VERSION 5.8 ;
BUSBITCHARS "[]" ;
DIVIDERCHAR "/" ;
UNITS
    DATABASE MICRONS 1000 ;
END UNITS

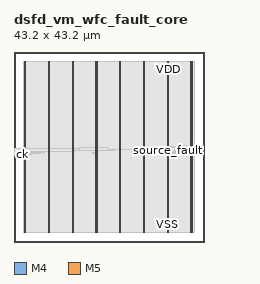
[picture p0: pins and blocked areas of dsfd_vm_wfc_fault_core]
MACRO dsfd_vm_wfc_fault_core
  FOREIGN dsfd_vm_wfc_fault_core 0 0 ;
  CLASS BLOCK ;
  SIZE 43.2 BY 43.2 ;
  PIN ck
    DIRECTION INPUT ;
    USE SIGNAL ;
    PORT
      LAYER M4 ;
        RECT  0 19.824 0.084 19.848 ;
    END
  END ck
  PIN core_fault
    DIRECTION INPUT ;
    USE SIGNAL ;
    PORT
      LAYER M4 ;
        RECT  0 19.92 0.084 19.944 ;
    END
  END core_fault
  PIN core_fault_b
    DIRECTION INPUT ;
    USE SIGNAL ;
    PORT
      LAYER M4 ;
        RECT  0 20.016 0.084 20.04 ;
    END
  END core_fault_b
  PIN remote_fault
    DIRECTION INPUT ;
    USE SIGNAL ;
    PORT
      LAYER M4 ;
        RECT  0 20.112 0.084 20.136 ;
    END
  END remote_fault
  PIN rn
    DIRECTION INPUT ;
    USE SIGNAL ;
    PORT
      LAYER M4 ;
        RECT  0 20.208 0.084 20.232 ;
    END
  END rn
  PIN source_fault
    DIRECTION OUTPUT ;
    USE SIGNAL ;
    PORT
      LAYER M4 ;
        RECT  43.116 20.784 43.2 20.808 ;
    END
  END source_fault
  PIN summary
    DIRECTION OUTPUT ;
    USE SIGNAL ;
    PORT
      LAYER M4 ;
        RECT  43.116 20.88 43.2 20.904 ;
    END
  END summary
  PIN transfer_fault
    DIRECTION INPUT ;
    USE SIGNAL ;
    PORT
      LAYER M4 ;
        RECT  0 20.304 0.084 20.328 ;
    END
  END transfer_fault
  PIN tx_valid
    DIRECTION OUTPUT ;
    USE SIGNAL ;
    PORT
      LAYER M4 ;
        RECT  43.116 20.976 43.2 21 ;
    END
  END tx_valid
  PIN VDD
    DIRECTION INOUT ;
    USE POWER ;
    PORT
      LAYER M5 ;
        RECT  40.392 2.151 40.512 41.049 ;
        RECT  34.992 2.151 35.112 41.049 ;
        RECT  29.592 2.151 29.712 41.049 ;
        RECT  24.192 2.151 24.312 41.049 ;
        RECT  18.792 2.151 18.912 41.049 ;
        RECT  13.392 2.151 13.512 41.049 ;
        RECT  7.992 2.151 8.112 41.049 ;
        RECT  2.592 2.151 2.712 41.049 ;
    END
  END VDD
  PIN VSS
    DIRECTION INOUT ;
    USE GROUND ;
    PORT
      LAYER M5 ;
        RECT  40.2 2.137 40.32 41.063 ;
        RECT  34.8 2.137 34.92 41.063 ;
        RECT  29.4 2.137 29.52 41.063 ;
        RECT  24 2.137 24.12 41.063 ;
        RECT  18.6 2.137 18.72 41.063 ;
        RECT  13.2 2.137 13.32 41.063 ;
        RECT  7.8 2.137 7.92 41.063 ;
        RECT  2.4 2.137 2.52 41.063 ;
    END
  END VSS
  # OT_OBS_CLOSED layer=M5 d_um=1.536 added=2
  OBS
    LAYER RVTN ;
     RECT  2.16 2.16 41.04 2.295 ;
     RECT  2.16 2.565 41.04 2.835 ;
     RECT  2.16 3.105 41.04 3.375 ;
     RECT  2.16 3.645 41.04 3.915 ;
     RECT  2.16 4.185 41.04 4.455 ;
     RECT  2.16 4.725 41.04 4.995 ;
     RECT  2.16 5.265 41.04 5.535 ;
     RECT  2.16 5.805 41.04 6.075 ;
     RECT  2.16 6.345 41.04 6.615 ;
     RECT  2.16 6.885 41.04 7.155 ;
     RECT  2.16 7.425 41.04 7.695 ;
     RECT  2.16 7.965 41.04 8.235 ;
     RECT  2.16 8.505 41.04 8.775 ;
     RECT  2.16 9.045 41.04 9.315 ;
     RECT  2.16 9.585 41.04 9.855 ;
     RECT  2.16 10.125 41.04 10.395 ;
     RECT  2.16 10.665 41.04 10.935 ;
     RECT  2.16 11.205 41.04 11.475 ;
     RECT  2.16 11.745 41.04 12.015 ;
     RECT  2.16 12.285 41.04 12.555 ;
     RECT  2.16 12.825 41.04 13.095 ;
     RECT  2.16 13.365 41.04 13.635 ;
     RECT  2.16 13.905 41.04 14.175 ;
     RECT  2.16 14.445 41.04 14.715 ;
     RECT  2.16 14.985 41.04 15.255 ;
     RECT  2.16 15.525 41.04 15.795 ;
     RECT  2.16 16.065 41.04 16.335 ;
     RECT  2.16 16.605 41.04 16.875 ;
     RECT  2.16 17.145 41.04 17.415 ;
     RECT  2.16 17.685 41.04 17.955 ;
     RECT  2.16 18.225 41.04 18.495 ;
     RECT  2.16 18.765 41.04 19.035 ;
     RECT  2.16 19.305 41.04 19.575 ;
     RECT  2.16 19.845 41.04 20.115 ;
     RECT  2.16 20.385 41.04 20.655 ;
     RECT  2.16 20.925 41.04 21.195 ;
     RECT  2.16 21.465 41.04 21.735 ;
     RECT  2.16 22.005 41.04 22.275 ;
     RECT  2.16 22.545 41.04 22.815 ;
     RECT  2.16 23.085 41.04 23.355 ;
     RECT  2.16 23.625 41.04 23.895 ;
     RECT  2.16 24.165 41.04 24.435 ;
     RECT  2.16 24.705 41.04 24.975 ;
     RECT  2.16 25.245 41.04 25.515 ;
     RECT  2.16 25.785 41.04 26.055 ;
     RECT  2.16 26.325 41.04 26.595 ;
     RECT  2.16 26.865 41.04 27.135 ;
     RECT  2.16 27.405 41.04 27.675 ;
     RECT  2.16 27.945 41.04 28.215 ;
     RECT  2.16 28.485 41.04 28.755 ;
     RECT  2.16 29.025 41.04 29.295 ;
     RECT  2.16 29.565 41.04 29.835 ;
     RECT  2.16 30.105 41.04 30.375 ;
     RECT  2.16 30.645 41.04 30.915 ;
     RECT  2.16 31.185 41.04 31.455 ;
     RECT  2.16 31.725 41.04 31.995 ;
     RECT  2.16 32.265 41.04 32.535 ;
     RECT  2.16 32.805 41.04 33.075 ;
     RECT  2.16 33.345 41.04 33.615 ;
     RECT  2.16 33.885 41.04 34.155 ;
     RECT  2.16 34.425 41.04 34.695 ;
     RECT  2.16 34.965 41.04 35.235 ;
     RECT  2.16 35.505 41.04 35.775 ;
     RECT  2.16 36.045 41.04 36.315 ;
     RECT  2.16 36.585 41.04 36.855 ;
     RECT  2.16 37.125 41.04 37.395 ;
     RECT  2.16 37.665 41.04 37.935 ;
     RECT  2.16 38.205 41.04 38.475 ;
     RECT  2.16 38.745 41.04 39.015 ;
     RECT  2.16 39.285 41.04 39.555 ;
     RECT  2.16 39.825 41.04 40.095 ;
     RECT  2.16 40.365 41.04 40.635 ;
     RECT  2.16 40.905 41.04 41.04 ;
    LAYER RVTP ;
     RECT  2.16 2.295 41.04 2.565 ;
     RECT  2.16 2.835 41.04 3.105 ;
     RECT  2.16 3.375 41.04 3.645 ;
     RECT  2.16 3.915 41.04 4.185 ;
     RECT  2.16 4.455 41.04 4.725 ;
     RECT  2.16 4.995 41.04 5.265 ;
     RECT  2.16 5.535 41.04 5.805 ;
     RECT  2.16 6.075 41.04 6.345 ;
     RECT  2.16 6.615 41.04 6.885 ;
     RECT  2.16 7.155 41.04 7.425 ;
     RECT  2.16 7.695 41.04 7.965 ;
     RECT  2.16 8.235 41.04 8.505 ;
     RECT  2.16 8.775 41.04 9.045 ;
     RECT  2.16 9.315 41.04 9.585 ;
     RECT  2.16 9.855 41.04 10.125 ;
     RECT  2.16 10.395 41.04 10.665 ;
     RECT  2.16 10.935 41.04 11.205 ;
     RECT  2.16 11.475 41.04 11.745 ;
     RECT  2.16 12.015 41.04 12.285 ;
     RECT  2.16 12.555 41.04 12.825 ;
     RECT  2.16 13.095 41.04 13.365 ;
     RECT  2.16 13.635 41.04 13.905 ;
     RECT  2.16 14.175 41.04 14.445 ;
     RECT  2.16 14.715 41.04 14.985 ;
     RECT  2.16 15.255 41.04 15.525 ;
     RECT  2.16 15.795 41.04 16.065 ;
     RECT  2.16 16.335 41.04 16.605 ;
     RECT  2.16 16.875 41.04 17.145 ;
     RECT  2.16 17.415 41.04 17.685 ;
     RECT  2.16 17.955 41.04 18.225 ;
     RECT  2.16 18.495 41.04 18.765 ;
     RECT  2.16 19.035 41.04 19.305 ;
     RECT  2.16 19.575 41.04 19.845 ;
     RECT  2.16 20.115 41.04 20.385 ;
     RECT  2.16 20.655 41.04 20.925 ;
     RECT  2.16 21.195 41.04 21.465 ;
     RECT  2.16 21.735 41.04 22.005 ;
     RECT  2.16 22.275 41.04 22.545 ;
     RECT  2.16 22.815 41.04 23.085 ;
     RECT  2.16 23.355 41.04 23.625 ;
     RECT  2.16 23.895 41.04 24.165 ;
     RECT  2.16 24.435 41.04 24.705 ;
     RECT  2.16 24.975 41.04 25.245 ;
     RECT  2.16 25.515 41.04 25.785 ;
     RECT  2.16 26.055 41.04 26.325 ;
     RECT  2.16 26.595 41.04 26.865 ;
     RECT  2.16 27.135 41.04 27.405 ;
     RECT  2.16 27.675 41.04 27.945 ;
     RECT  2.16 28.215 41.04 28.485 ;
     RECT  2.16 28.755 41.04 29.025 ;
     RECT  2.16 29.295 41.04 29.565 ;
     RECT  2.16 29.835 41.04 30.105 ;
     RECT  2.16 30.375 41.04 30.645 ;
     RECT  2.16 30.915 41.04 31.185 ;
     RECT  2.16 31.455 41.04 31.725 ;
     RECT  2.16 31.995 41.04 32.265 ;
     RECT  2.16 32.535 41.04 32.805 ;
     RECT  2.16 33.075 41.04 33.345 ;
     RECT  2.16 33.615 41.04 33.885 ;
     RECT  2.16 34.155 41.04 34.425 ;
     RECT  2.16 34.695 41.04 34.965 ;
     RECT  2.16 35.235 41.04 35.505 ;
     RECT  2.16 35.775 41.04 36.045 ;
     RECT  2.16 36.315 41.04 36.585 ;
     RECT  2.16 36.855 41.04 37.125 ;
     RECT  2.16 37.395 41.04 37.665 ;
     RECT  2.16 37.935 41.04 38.205 ;
     RECT  2.16 38.475 41.04 38.745 ;
     RECT  2.16 39.015 41.04 39.285 ;
     RECT  2.16 39.555 41.04 39.825 ;
     RECT  2.16 40.095 41.04 40.365 ;
     RECT  2.16 40.635 41.04 40.905 ;
    LAYER M1 ;
     RECT  2.16 2.151 41.04 41.049 ;
    LAYER M2 ;
     RECT  2.16 2.151 41.04 41.049 ;
     RECT  41.04 20.736 42.179 21.924 ;
     RECT  42.179 21.906 43.115 21.924 ;
    LAYER M3 ;
     RECT  2.415 2.143 2.505 2.413 ;
     RECT  7.815 2.143 7.905 2.413 ;
     RECT  13.215 2.143 13.305 2.413 ;
     RECT  18.615 2.143 18.705 2.413 ;
     RECT  24.015 2.143 24.105 2.413 ;
     RECT  29.415 2.143 29.505 2.413 ;
     RECT  34.815 2.143 34.905 2.413 ;
     RECT  40.215 2.143 40.305 2.413 ;
     RECT  2.415 2.413 2.697 19.885 ;
     RECT  3.528 19.885 4.086 19.921 ;
     RECT  34.815 2.413 35.097 20.011 ;
     RECT  3.42 19.921 4.086 20.119 ;
     RECT  5.652 19.885 5.67 20.119 ;
     RECT  34.815 20.011 35.442 20.119 ;
     RECT  2.304 19.885 2.697 20.155 ;
     RECT  3.42 20.119 4.23 20.155 ;
     RECT  6.912 20.119 6.93 20.155 ;
     RECT  18.615 2.413 18.897 20.155 ;
     RECT  32.976 20.083 32.994 20.155 ;
     RECT  34.776 20.119 35.946 20.155 ;
     RECT  37.224 20.119 37.242 20.155 ;
     RECT  2.304 20.155 4.842 20.191 ;
     RECT  5.652 20.119 5.814 20.191 ;
     RECT  34.776 20.155 37.386 20.191 ;
     RECT  6.912 20.155 6.966 20.309 ;
     RECT  17.892 20.155 18.897 20.309 ;
     RECT  2.304 20.191 6.138 20.317 ;
     RECT  6.912 20.309 6.93 20.317 ;
     RECT  29.415 2.413 29.697 20.317 ;
     RECT  30.528 20.083 30.834 20.317 ;
     RECT  32.94 20.155 32.994 20.317 ;
     RECT  13.215 2.413 13.497 20.389 ;
     RECT  34.272 20.191 37.926 20.389 ;
     RECT  2.304 20.317 6.93 20.417 ;
     RECT  28.296 20.281 28.314 20.425 ;
     RECT  31.572 20.317 31.59 20.461 ;
     RECT  32.328 20.317 32.994 20.461 ;
     RECT  33.984 20.389 37.926 20.461 ;
     RECT  39.06 20.353 39.078 20.461 ;
     RECT  40.215 2.413 40.497 20.461 ;
     RECT  2.304 20.417 6.318 20.489 ;
     RECT  10.836 20.389 10.854 20.489 ;
     RECT  13.215 20.389 13.77 20.489 ;
     RECT  2.304 20.489 6.174 20.579 ;
     RECT  31.572 20.461 32.994 20.615 ;
     RECT  26.784 20.155 26.802 20.659 ;
     RECT  29.304 20.317 30.834 20.659 ;
     RECT  4.068 20.579 6.174 20.669 ;
     RECT  4.068 20.669 4.23 20.687 ;
     RECT  33.984 20.461 39.078 20.695 ;
     RECT  40.068 20.461 40.497 20.695 ;
     RECT  2.304 20.579 3.294 20.723 ;
     RECT  4.068 20.687 4.086 20.723 ;
     RECT  5.004 20.669 6.174 20.723 ;
     RECT  26.784 20.659 27.45 20.731 ;
     RECT  28.296 20.425 28.35 20.731 ;
     RECT  29.088 20.659 30.834 20.731 ;
     RECT  31.572 20.615 31.734 20.731 ;
     RECT  32.472 20.615 32.994 20.731 ;
     RECT  33.984 20.695 39.258 20.731 ;
     RECT  2.304 20.723 3.15 20.849 ;
     RECT  5.004 20.723 5.022 20.849 ;
     RECT  5.796 20.723 6.174 20.849 ;
     RECT  13.215 20.489 13.662 20.861 ;
     RECT  26.784 20.731 31.734 20.885 ;
     RECT  32.472 20.731 39.258 20.885 ;
     RECT  2.304 20.849 2.697 20.921 ;
     RECT  26.784 20.885 27.45 20.921 ;
     RECT  22.824 20.827 22.842 20.957 ;
     RECT  26.784 20.921 26.874 20.957 ;
     RECT  37.152 20.885 39.258 21.001 ;
     RECT  40.068 20.695 40.734 21.001 ;
     RECT  26.856 20.957 26.874 21.005 ;
     RECT  28.224 20.885 31.734 21.119 ;
     RECT  37.152 21.001 40.734 21.119 ;
     RECT  28.224 21.119 30.438 21.155 ;
     RECT  21.132 21.115 21.15 21.163 ;
     RECT  28.296 21.155 30.438 21.191 ;
     RECT  20.916 21.163 21.15 21.2 ;
     RECT  31.284 21.119 31.41 21.263 ;
     RECT  28.296 21.191 29.754 21.389 ;
     RECT  31.392 21.263 31.41 21.389 ;
     RECT  32.472 20.885 35.946 21.389 ;
     RECT  28.296 21.389 29.697 21.395 ;
     RECT  33.48 21.389 35.097 21.425 ;
     RECT  14.832 21.307 14.85 21.437 ;
     RECT  21.132 21.2 21.15 21.437 ;
     RECT  32.472 21.389 32.742 21.437 ;
     RECT  33.66 21.425 35.097 21.437 ;
     RECT  28.512 21.395 29.697 21.461 ;
     RECT  42.156 20.731 42.174 21.497 ;
     RECT  28.512 21.461 28.53 21.569 ;
     RECT  37.152 21.119 40.698 21.631 ;
     RECT  32.472 21.437 32.49 21.659 ;
     RECT  33.66 21.437 33.678 21.659 ;
     RECT  35.928 21.389 35.946 21.659 ;
     RECT  37.044 21.631 40.698 21.695 ;
     RECT  37.044 21.695 39.222 21.739 ;
     RECT  36.54 21.739 39.222 21.803 ;
     RECT  37.044 21.803 39.222 21.929 ;
     RECT  43.092 20.971 43.11 21.929 ;
     RECT  37.224 21.929 37.71 21.965 ;
     RECT  40.215 21.695 40.698 21.965 ;
     RECT  38.664 21.929 39.222 22.001 ;
     RECT  38.664 22.001 38.682 22.037 ;
     RECT  37.224 21.965 37.674 22.073 ;
     RECT  37.224 22.073 37.386 22.199 ;
     RECT  37.224 22.199 37.242 22.235 ;
     RECT  2.415 20.921 2.697 40.787 ;
     RECT  7.815 2.413 8.097 40.787 ;
     RECT  13.215 20.861 13.497 40.787 ;
     RECT  18.615 20.309 18.897 40.787 ;
     RECT  24.015 2.413 24.297 40.787 ;
     RECT  29.415 21.461 29.697 40.787 ;
     RECT  34.815 21.437 35.097 40.787 ;
     RECT  40.215 21.965 40.497 40.787 ;
     RECT  2.415 40.787 2.505 41.057 ;
     RECT  7.815 40.787 7.905 41.057 ;
     RECT  13.215 40.787 13.305 41.057 ;
     RECT  18.615 40.787 18.705 41.057 ;
     RECT  24.015 40.787 24.105 41.057 ;
     RECT  29.415 40.787 29.505 41.057 ;
     RECT  34.815 40.787 34.905 41.057 ;
     RECT  40.215 40.787 40.305 41.057 ;
    LAYER M4 ;
     RECT  0.084 19.824 0.133 19.848 ;
     RECT  0.06 19.848 0.133 19.92 ;
     RECT  0.084 19.92 0.133 19.944 ;
     RECT  0.06 19.944 0.133 20.016 ;
     RECT  0.084 20.016 0.133 20.04 ;
     RECT  0.06 20.04 0.133 20.112 ;
     RECT  0.084 20.112 0.133 20.136 ;
     RECT  0.06 20.136 0.133 20.208 ;
     RECT  0.084 20.208 0.133 20.232 ;
     RECT  0.06 20.232 0.133 20.304 ;
     RECT  0.084 20.304 0.133 20.328 ;
     RECT  0.133 19.824 0.179 21.192 ;
     RECT  0.179 19.92 2.408 21.192 ;
     RECT  2.408 2.148 2.512 41.052 ;
     RECT  2.512 2.418 2.704 40.782 ;
     RECT  2.704 20.64 7.808 21.192 ;
     RECT  7.808 2.148 7.912 41.052 ;
     RECT  7.912 2.418 8.104 40.782 ;
     RECT  8.104 20.64 13.208 21.192 ;
     RECT  13.208 2.148 13.312 41.052 ;
     RECT  13.312 2.418 13.504 40.782 ;
     RECT  13.504 20.448 13.667 21.336 ;
     RECT  13.667 20.832 14.821 21.336 ;
     RECT  14.821 20.832 18.608 21.432 ;
     RECT  18.608 2.148 18.712 41.052 ;
     RECT  18.712 2.418 18.904 40.782 ;
     RECT  18.904 20.832 21.161 21.432 ;
     RECT  21.161 20.832 22.853 21.144 ;
     RECT  22.853 20.928 24.008 21.144 ;
     RECT  24.008 2.148 24.112 41.052 ;
     RECT  24.112 2.418 24.304 40.782 ;
     RECT  24.304 20.928 26.829 21.144 ;
     RECT  26.829 20.976 26.869 21.144 ;
     RECT  26.869 20.976 26.915 21.384 ;
     RECT  26.915 21.12 29.269 21.384 ;
     RECT  29.269 20.352 29.408 21.384 ;
     RECT  29.408 2.148 29.512 41.052 ;
     RECT  29.512 2.418 29.704 40.782 ;
     RECT  29.704 20.448 31.532 21.192 ;
     RECT  31.532 20.352 31.573 21.192 ;
     RECT  31.573 20.352 31.619 21.432 ;
     RECT  31.619 21.408 34.808 21.432 ;
     RECT  34.808 2.148 34.912 41.052 ;
     RECT  34.912 2.418 35.104 40.782 ;
     RECT  35.104 20.304 35.219 21.432 ;
     RECT  35.219 20.448 35.273 20.712 ;
     RECT  35.273 20.688 36.529 20.712 ;
     RECT  36.529 20.496 37.289 20.712 ;
     RECT  37.289 20.688 37.793 20.712 ;
     RECT  36.517 21.744 37.973 21.768 ;
     RECT  40.208 2.148 40.312 41.052 ;
     RECT  40.312 2.418 40.504 40.782 ;
     RECT  42.145 20.784 43.081 20.904 ;
     RECT  43.081 20.784 43.116 20.808 ;
     RECT  43.081 20.808 43.164 20.88 ;
     RECT  43.081 20.88 43.116 20.904 ;
     RECT  43.081 20.904 43.164 20.976 ;
     RECT  43.081 20.976 43.116 21 ;
    LAYER M5 ;
     RECT  2.4 2.137 2.52 2.151 ;
     RECT  7.8 2.137 7.92 2.151 ;
     RECT  13.2 2.137 13.32 2.151 ;
     RECT  18.6 2.137 18.72 2.151 ;
     RECT  24 2.137 24.12 2.151 ;
     RECT  29.4 2.137 29.52 2.151 ;
     RECT  34.8 2.137 34.92 2.151 ;
     RECT  40.2 2.137 40.32 2.151 ;
     RECT  34.8 2.151 35.112 20.293 ;
     RECT  29.4 2.151 29.712 20.341 ;
     RECT  13.2 2.151 13.512 20.437 ;
     RECT  0.144 19.813 0.168 21.203 ;
     RECT  13.2 20.437 13.656 21.347 ;
     RECT  26.88 20.965 26.904 21.395 ;
     RECT  29.28 20.341 29.712 21.395 ;
     RECT  31.584 20.341 31.608 21.443 ;
     RECT  34.8 20.293 35.208 21.443 ;
     RECT  36.528 20.677 36.552 21.779 ;
     RECT  2.4 2.151 2.712 41.049 ;
     RECT  7.8 2.151 8.112 41.049 ;
     RECT  13.2 21.347 13.512 41.049 ;
     RECT  18.6 2.151 18.912 41.049 ;
     RECT  24 2.151 24.312 41.049 ;
     RECT  29.4 21.395 29.712 41.049 ;
     RECT  34.8 21.443 35.112 41.049 ;
     RECT  40.2 2.151 40.512 41.049 ;
     RECT  2.4 41.049 2.52 41.063 ;
     RECT  7.8 41.049 7.92 41.063 ;
     RECT  13.2 41.049 13.32 41.063 ;
     RECT  18.6 41.049 18.72 41.063 ;
     RECT  24 41.049 24.12 41.063 ;
     RECT  29.4 41.049 29.52 41.063 ;
     RECT  34.8 41.049 34.92 41.063 ;
     RECT  40.2 41.049 40.32 41.063 ;
     RECT  35.208 20.677 36.528 21.443 ;
     RECT  35.112 21.443 36.528 21.779 ;
  END
END dsfd_vm_wfc_fault_core
END LIBRARY
